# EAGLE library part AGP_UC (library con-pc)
AGP:UC Slot AMP connctor 145376 >PCT-GF40< 132 Position 1mm, card edge connector Drawing No: C-145263 Source: http://ecommas.tycoelectronics.com .. ENG_CD_145376_D.pdf

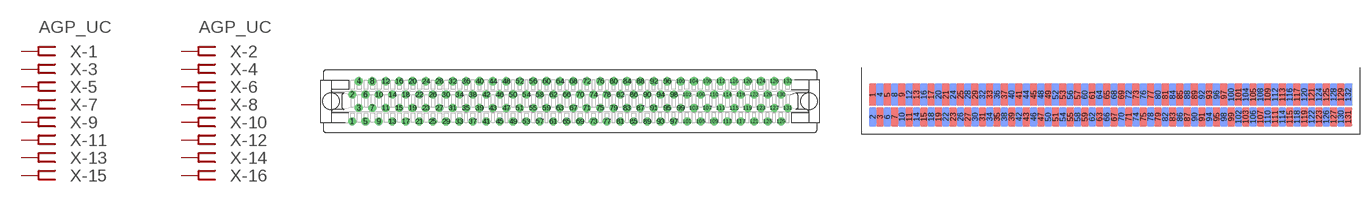
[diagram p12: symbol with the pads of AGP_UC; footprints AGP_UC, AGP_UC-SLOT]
Designator prefix X; gates -1=FEMRVAL -2=FEMRVAL -3=FEMREC -4=FEMREC -5=FEMREC -6=FEMREC -7=FEMREC -8=FEMREC -9=FEMREC -10=FEMREC -11=FEMREC -12=FEMREC -13=FEMREC -14=FEMREC -15=FEMREC -16=FEMREC -17=FEMREC -18=FEMREC -19=FEMREC -20=FEMREC -21=FEMREC -22=FEMREC -23=FEMREC -24=FEMREC -25=FEMREC -26=FEMREC -27=FEMREC -28=FEMREC -29=FEMREC -30=FEMREC -31=FEMREC -32=FEMREC -33=FEMREC -34=FEMREC -35=FEMREC -36=FEMREC -37=FEMREC -38=FEMREC -39=FEMREC -40=FEMREC -41=FEMREC -42=FEMREC -43=FEMREC -44=FEMREC -45=FEMREC -46=FEMREC -47=FEMREC -48=FEMREC -49=FEMREC -50=FEMREC -51=FEMREC -52=FEMREC -53=FEMREC -54=FEMREC -55=FEMREC -56=FEMREC -57=FEMREC -58=FEMREC -59=FEMREC -60=FEMREC -61=FEMREC -62=FEMREC -63=FEMREC -64=FEMREC -65=FEMREC -66=FEMREC -67=FEMREC -68=FEMREC -69=FEMREC -70=FEMREC -71=FEMREC -72=FEMREC -73=FEMREC -74=FEMREC -75=FEMREC -76=FEMREC -77=FEMREC -78=FEMREC -79=FEMREC -80=FEMREC -81=FEMREC -82=FEMREC -83=FEMREC -84=FEMREC -85=FEMREC -86=FEMREC -87=FEMREC -88=FEMREC -89=FEMREC -90=FEMREC -91=FEMREC -92=FEMREC -93=FEMREC -94=FEMREC -95=FEMREC -96=FEMREC -97=FEMREC -98=FEMREC -99=FEMREC -100=FEMREC -101=FEMREC -102=FEMREC -103=FEMREC -104=FEMREC -105=FEMREC -106=FEMREC -107=FEMREC -108=FEMREC -109=FEMREC -110=FEMREC -111=FEMREC -112=FEMREC -113=FEMREC -114=FEMREC -115=FEMREC -116=FEMREC -117=FEMREC -118=FEMREC -119=FEMREC -120=FEMREC -121=FEMREC -122=FEMREC -123=FEMREC -124=FEMREC -125=FEMREC -126=FEMREC -127=FEMREC -128=FEMREC -129=FEMREC -130=FEMREC -131=FEMREC -132=FEMREC

## AGP_UC  [AGP_UC]
1  -1:P  pas
2  -2:P  pas
3  -3:P  pas
4  -4:P  pas
5  -5:P  pas
6  -6:P  pas
7  -7:P  pas
8  -8:P  pas
9  -9:P  pas
10  -10:P  pas
11  -11:P  pas
12  -12:P  pas
13  -13:P  pas
14  -14:P  pas
15  -15:P  pas
16  -16:P  pas
17  -17:P  pas
18  -18:P  pas
19  -19:P  pas
20  -20:P  pas
21  -21:P  pas
22  -22:P  pas
23  -23:P  pas
24  -24:P  pas
25  -25:P  pas
26  -26:P  pas
27  -27:P  pas
28  -28:P  pas
29  -29:P  pas
30  -30:P  pas
31  -31:P  pas
32  -32:P  pas
33  -33:P  pas
34  -34:P  pas
35  -35:P  pas
36  -36:P  pas
37  -37:P  pas
38  -38:P  pas
39  -39:P  pas
40  -40:P  pas
41  -41:P  pas
42  -42:P  pas
43  -43:P  pas
44  -44:P  pas
45  -45:P  pas
46  -46:P  pas
47  -47:P  pas
48  -48:P  pas
49  -49:P  pas
50  -50:P  pas
51  -51:P  pas
52  -52:P  pas
53  -53:P  pas
54  -54:P  pas
55  -55:P  pas
56  -56:P  pas
57  -57:P  pas
58  -58:P  pas
59  -59:P  pas
60  -60:P  pas
61  -61:P  pas
62  -62:P  pas
63  -63:P  pas
64  -64:P  pas
65  -65:P  pas
66  -66:P  pas
67  -67:P  pas
68  -68:P  pas
69  -69:P  pas
70  -70:P  pas
71  -71:P  pas
72  -72:P  pas
73  -73:P  pas
74  -74:P  pas
75  -75:P  pas
76  -76:P  pas
77  -77:P  pas
78  -78:P  pas
79  -79:P  pas
80  -80:P  pas
81  -81:P  pas
82  -82:P  pas
83  -83:P  pas
84  -84:P  pas
85  -85:P  pas
86  -86:P  pas
87  -87:P  pas
88  -88:P  pas
89  -89:P  pas
90  -90:P  pas
91  -91:P  pas
92  -92:P  pas
93  -93:P  pas
94  -94:P  pas
95  -95:P  pas
96  -96:P  pas
97  -97:P  pas
98  -98:P  pas
99  -99:P  pas
100  -100:P  pas
101  -101:P  pas
102  -102:P  pas
103  -103:P  pas
104  -104:P  pas
105  -105:P  pas
106  -106:P  pas
107  -107:P  pas
108  -108:P  pas
109  -109:P  pas
110  -110:P  pas
111  -111:P  pas
112  -112:P  pas
113  -113:P  pas
114  -114:P  pas
115  -115:P  pas
116  -116:P  pas
117  -117:P  pas
118  -118:P  pas
119  -119:P  pas
120  -120:P  pas
121  -121:P  pas
122  -122:P  pas
123  -123:P  pas
124  -124:P  pas
125  -125:P  pas
126  -126:P  pas
127  -127:P  pas
128  -128:P  pas
129  -129:P  pas
130  -130:P  pas
131  -131:P  pas
132  -132:P  pas

## AGP_UC-SLOT  [AGP_UC-SLOT]
Pads as for AGP_UC

## Footprint AGP_UC (pad centres in mm)
AGP:UC Slot AMP connctor 145376 >PCT-GF40< 132 Position 1mm, card edge connector Drawing No: C-145263 Source: http://ecommas.tycoelectronics.com .. ENG_CD_145376_D.pdf
drill 0.7 pad 1.1 round: 1 0,-3; 2 0,1; 3 1,-1; 4 1,3; 5 2,-3; 6 2,1; 7 3,-1; 8 3,3; 9 4,-3; 10 4,1; 11 5,-1; 12 5,3; 13 6,-3; 14 6,1; 15 7,-1; 16 7,3; 17 8,-3; 18 8,1; 19 9,-1; 20 9,3; 21 10,-3; 22 10,1; 23 11,-1; 24 11,3; 25 12,-3; 26 12,1; 27 13,-1; 28 13,3; 29 14,-3; 30 14,1; 31 15,-1; 32 15,3; 33 16,-3; 34 16,1; 35 17,-1; 36 17,3; 37 18,-3; 38 18,1; 39 19,-1; 40 19,3; 41 20,-3; 42 20,1; 43 21,-1; 44 21,3; 45 22,-3; 46 22,1; 47 23,-1; 48 23,3; 49 24,-3; 50 24,1; 51 25,-1; 52 25,3; 53 26,-3; 54 26,1; 55 27,-1; 56 27,3; 57 28,-3; 58 28,1; 59 29,-1; 60 29,3; 61 30,-3; 62 30,1; 63 31,-1; 64 31,3; 65 32,-3; 66 32,1; 67 33,-1; 68 33,3; 69 34,-3; 70 34,1; 71 35,-1; 72 35,3; 73 36,-3; 74 36,1; 75 37,-1; 76 37,3; 77 38,-3; 78 38,1; 79 39,-1; 80 39,3; 81 40,-3; 82 40,1; 83 41,-1; 84 41,3; 85 42,-3; 86 42,1; 87 43,-1; 88 43,3; 89 44,-3; 90 44,1; 91 45,-1; 92 45,3; 93 46,-3; 94 46,1; 95 47,-1; 96 47,3; 97 48,-3; 98 48,1; 99 49,-1; 100 49,3; 101 50,-3; 102 50,1; 103 51,-1; 104 51,3; 105 52,-3; 106 52,1; 107 53,-1; 108 53,3; 109 54,-3; 110 54,1; 111 55,-1; 112 55,3; 113 56,-3; 114 56,1; 115 57,-1; 116 57,3; 117 58,-3; 118 58,1; 119 59,-1; 120 59,3; 121 60,-3; 122 60,1; 123 61,-1; 124 61,3; 125 62,-3; 126 62,1; 127 63,-1; 128 63,3; 129 64,-3; 130 64,1; 131 65,-1; 132 65,3
hole 2.5 at -3.14,0
hole 2.5 at 68.14,0

## Footprint AGP_UC-SLOT (pad centres in mm)
AGP:UC 132 Position 1mm Card connector Drawing No: C-145376 Source: http://ecommas.tycoelectronics.com .. ENG_CD_145376_D.pdf
smd 1.09 x 3.09: 1 1.54,5.46; 5 3.54,5.46; 9 5.54,5.46; 13 7.54,5.46; 17 9.54,5.46; 21 11.54,5.46; 25 13.54,5.46; 29 15.54,5.46; 33 17.54,5.46; 37 19.54,5.46; 41 21.54,5.46; 45 23.54,5.46; 49 25.54,5.46; 53 27.54,5.46; 57 29.54,5.46; 61 31.54,5.46; 65 33.54,5.46; 69 35.54,5.46; 73 37.54,5.46; 77 39.54,5.46; 81 41.54,5.46; 85 43.54,5.46; 89 45.54,5.46; 93 47.54,5.46; 97 49.54,5.46; 101 51.54,5.46; 105 53.54,5.46; 109 55.54,5.46; 113 57.54,5.46; 117 59.54,5.46; 121 61.54,5.46; 125 63.54,5.46; 129 65.54,5.46
smd 1.09 x 2.56 bottom: 2 1.54,2.42; 6 3.54,2.42; 10 5.54,2.42; 14 7.54,2.42; 18 9.54,2.42; 22 11.54,2.42; 26 13.54,2.42; 30 15.54,2.42; 34 17.54,2.42; 38 19.54,2.42; 42 21.54,2.42; 46 23.54,2.42; 50 25.54,2.42; 54 27.54,2.42; 58 29.54,2.42; 62 31.54,2.42; 66 33.54,2.42; 70 35.54,2.42; 74 37.54,2.42; 78 39.54,2.42; 82 41.54,2.42; 86 43.54,2.42; 90 45.54,2.42; 94 47.54,2.42; 98 49.54,2.42; 102 51.54,2.42; 106 53.54,2.42; 110 55.54,2.42; 114 57.54,2.42; 118 59.54,2.42; 122 61.54,2.42; 126 63.54,2.42; 130 65.54,2.42
smd 1.09 x 2.56: 3 2.54,2.42; 7 4.54,2.42; 11 6.54,2.42; 15 8.54,2.42; 19 10.54,2.42; 23 12.54,2.42; 27 14.54,2.42; 31 16.54,2.42; 35 18.54,2.42; 39 20.54,2.42; 43 22.54,2.42; 47 24.54,2.42; 51 26.54,2.42; 55 28.54,2.42; 59 30.54,2.42; 63 32.54,2.42; 67 34.54,2.42; 71 36.54,2.42; 75 38.54,2.42; 79 40.54,2.42; 83 42.54,2.42; 87 44.54,2.42; 91 46.54,2.42; 95 48.54,2.42; 99 50.54,2.42; 103 52.54,2.42; 107 54.54,2.42; 111 56.54,2.42; 115 58.54,2.42; 119 60.54,2.42; 123 62.54,2.42; 127 64.54,2.42; 131 66.54,2.42
smd 1.09 x 3.09 bottom: 4 2.54,5.46; 8 4.54,5.46; 12 6.54,5.46; 16 8.54,5.46; 20 10.54,5.46; 24 12.54,5.46; 28 14.54,5.46; 32 16.54,5.46; 36 18.54,5.46; 40 20.54,5.46; 44 22.54,5.46; 48 24.54,5.46; 52 26.54,5.46; 56 28.54,5.46; 60 30.54,5.46; 64 32.54,5.46; 68 34.54,5.46; 72 36.54,5.46; 76 38.54,5.46; 80 40.54,5.46; 84 42.54,5.46; 88 44.54,5.46; 92 46.54,5.46; 96 48.54,5.46; 100 50.54,5.46; 104 52.54,5.46; 108 54.54,5.46; 112 56.54,5.46; 116 58.54,5.46; 120 60.54,5.46; 124 62.54,5.46; 128 64.54,5.46; 132 66.54,5.46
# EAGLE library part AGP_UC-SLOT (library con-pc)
AGP:UC Slot AMP connctor 145376 >PCT-GF40< 132 Position 1mm, card edge connector Drawing No: C-145263 Source: http://ecommas.tycoelectronics.com .. ENG_CD_145376_D.pdf

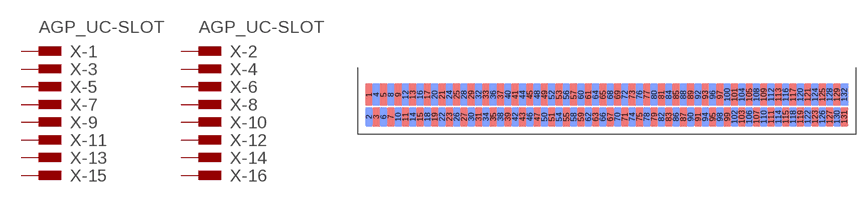
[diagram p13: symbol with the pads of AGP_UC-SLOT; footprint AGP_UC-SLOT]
Designator prefix X; gates -1=MALEVAL -2=MALEVAL -3=MALE -4=MALE -5=MALE -6=MALE -7=MALE -8=MALE -9=MALE -10=MALE -11=MALE -12=MALE -13=MALE -14=MALE -15=MALE -16=MALE -17=MALE -18=MALE -19=MALE -20=MALE -21=MALE -22=MALE -23=MALE -24=MALE -25=MALE -26=MALE -27=MALE -28=MALE -29=MALE -30=MALE -31=MALE -32=MALE -33=MALE -34=MALE -35=MALE -36=MALE -37=MALE -38=MALE -39=MALE -40=MALE -41=MALE -42=MALE -43=MALE -44=MALE -45=MALE -46=MALE -47=MALE -48=MALE -49=MALE -50=MALE -51=MALE -52=MALE -53=MALE -54=MALE -55=MALE -56=MALE -57=MALE -58=MALE -59=MALE -60=MALE -61=MALE -62=MALE -63=MALE -64=MALE -65=MALE -66=MALE -67=MALE -68=MALE -69=MALE -70=MALE -71=MALE -72=MALE -73=MALE -74=MALE -75=MALE -76=MALE -77=MALE -78=MALE -79=MALE -80=MALE -81=MALE -82=MALE -83=MALE -84=MALE -85=MALE -86=MALE -87=MALE -88=MALE -89=MALE -90=MALE -91=MALE -92=MALE -93=MALE -94=MALE -95=MALE -96=MALE -97=MALE -98=MALE -99=MALE -100=MALE -101=MALE -102=MALE -103=MALE -104=MALE -105=MALE -106=MALE -107=MALE -108=MALE -109=MALE -110=MALE -111=MALE -112=MALE -113=MALE -114=MALE -115=MALE -116=MALE -117=MALE -118=MALE -119=MALE -120=MALE -121=MALE -122=MALE -123=MALE -124=MALE -125=MALE -126=MALE -127=MALE -128=MALE -129=MALE -130=MALE -131=MALE -132=MALE

## AGP_UC-SLOT  [AGP_UC-SLOT]
1  -1:P  pas
2  -2:P  pas
3  -3:P  pas
4  -4:P  pas
5  -5:P  pas
6  -6:P  pas
7  -7:P  pas
8  -8:P  pas
9  -9:P  pas
10  -10:P  pas
11  -11:P  pas
12  -12:P  pas
13  -13:P  pas
14  -14:P  pas
15  -15:P  pas
16  -16:P  pas
17  -17:P  pas
18  -18:P  pas
19  -19:P  pas
20  -20:P  pas
21  -21:P  pas
22  -22:P  pas
23  -23:P  pas
24  -24:P  pas
25  -25:P  pas
26  -26:P  pas
27  -27:P  pas
28  -28:P  pas
29  -29:P  pas
30  -30:P  pas
31  -31:P  pas
32  -32:P  pas
33  -33:P  pas
34  -34:P  pas
35  -35:P  pas
36  -36:P  pas
37  -37:P  pas
38  -38:P  pas
39  -39:P  pas
40  -40:P  pas
41  -41:P  pas
42  -42:P  pas
43  -43:P  pas
44  -44:P  pas
45  -45:P  pas
46  -46:P  pas
47  -47:P  pas
48  -48:P  pas
49  -49:P  pas
50  -50:P  pas
51  -51:P  pas
52  -52:P  pas
53  -53:P  pas
54  -54:P  pas
55  -55:P  pas
56  -56:P  pas
57  -57:P  pas
58  -58:P  pas
59  -59:P  pas
60  -60:P  pas
61  -61:P  pas
62  -62:P  pas
63  -63:P  pas
64  -64:P  pas
65  -65:P  pas
66  -66:P  pas
67  -67:P  pas
68  -68:P  pas
69  -69:P  pas
70  -70:P  pas
71  -71:P  pas
72  -72:P  pas
73  -73:P  pas
74  -74:P  pas
75  -75:P  pas
76  -76:P  pas
77  -77:P  pas
78  -78:P  pas
79  -79:P  pas
80  -80:P  pas
81  -81:P  pas
82  -82:P  pas
83  -83:P  pas
84  -84:P  pas
85  -85:P  pas
86  -86:P  pas
87  -87:P  pas
88  -88:P  pas
89  -89:P  pas
90  -90:P  pas
91  -91:P  pas
92  -92:P  pas
93  -93:P  pas
94  -94:P  pas
95  -95:P  pas
96  -96:P  pas
97  -97:P  pas
98  -98:P  pas
99  -99:P  pas
100  -100:P  pas
101  -101:P  pas
102  -102:P  pas
103  -103:P  pas
104  -104:P  pas
105  -105:P  pas
106  -106:P  pas
107  -107:P  pas
108  -108:P  pas
109  -109:P  pas
110  -110:P  pas
111  -111:P  pas
112  -112:P  pas
113  -113:P  pas
114  -114:P  pas
115  -115:P  pas
116  -116:P  pas
117  -117:P  pas
118  -118:P  pas
119  -119:P  pas
120  -120:P  pas
121  -121:P  pas
122  -122:P  pas
123  -123:P  pas
124  -124:P  pas
125  -125:P  pas
126  -126:P  pas
127  -127:P  pas
128  -128:P  pas
129  -129:P  pas
130  -130:P  pas
131  -131:P  pas
132  -132:P  pas

## Footprint AGP_UC-SLOT (pad centres in mm)
AGP:UC 132 Position 1mm Card connector Drawing No: C-145376 Source: http://ecommas.tycoelectronics.com .. ENG_CD_145376_D.pdf
smd 1.09 x 3.09: 1 1.54,5.46; 5 3.54,5.46; 9 5.54,5.46; 13 7.54,5.46; 17 9.54,5.46; 21 11.54,5.46; 25 13.54,5.46; 29 15.54,5.46; 33 17.54,5.46; 37 19.54,5.46; 41 21.54,5.46; 45 23.54,5.46; 49 25.54,5.46; 53 27.54,5.46; 57 29.54,5.46; 61 31.54,5.46; 65 33.54,5.46; 69 35.54,5.46; 73 37.54,5.46; 77 39.54,5.46; 81 41.54,5.46; 85 43.54,5.46; 89 45.54,5.46; 93 47.54,5.46; 97 49.54,5.46; 101 51.54,5.46; 105 53.54,5.46; 109 55.54,5.46; 113 57.54,5.46; 117 59.54,5.46; 121 61.54,5.46; 125 63.54,5.46; 129 65.54,5.46
smd 1.09 x 2.56 bottom: 2 1.54,2.42; 6 3.54,2.42; 10 5.54,2.42; 14 7.54,2.42; 18 9.54,2.42; 22 11.54,2.42; 26 13.54,2.42; 30 15.54,2.42; 34 17.54,2.42; 38 19.54,2.42; 42 21.54,2.42; 46 23.54,2.42; 50 25.54,2.42; 54 27.54,2.42; 58 29.54,2.42; 62 31.54,2.42; 66 33.54,2.42; 70 35.54,2.42; 74 37.54,2.42; 78 39.54,2.42; 82 41.54,2.42; 86 43.54,2.42; 90 45.54,2.42; 94 47.54,2.42; 98 49.54,2.42; 102 51.54,2.42; 106 53.54,2.42; 110 55.54,2.42; 114 57.54,2.42; 118 59.54,2.42; 122 61.54,2.42; 126 63.54,2.42; 130 65.54,2.42
smd 1.09 x 2.56: 3 2.54,2.42; 7 4.54,2.42; 11 6.54,2.42; 15 8.54,2.42; 19 10.54,2.42; 23 12.54,2.42; 27 14.54,2.42; 31 16.54,2.42; 35 18.54,2.42; 39 20.54,2.42; 43 22.54,2.42; 47 24.54,2.42; 51 26.54,2.42; 55 28.54,2.42; 59 30.54,2.42; 63 32.54,2.42; 67 34.54,2.42; 71 36.54,2.42; 75 38.54,2.42; 79 40.54,2.42; 83 42.54,2.42; 87 44.54,2.42; 91 46.54,2.42; 95 48.54,2.42; 99 50.54,2.42; 103 52.54,2.42; 107 54.54,2.42; 111 56.54,2.42; 115 58.54,2.42; 119 60.54,2.42; 123 62.54,2.42; 127 64.54,2.42; 131 66.54,2.42
smd 1.09 x 3.09 bottom: 4 2.54,5.46; 8 4.54,5.46; 12 6.54,5.46; 16 8.54,5.46; 20 10.54,5.46; 24 12.54,5.46; 28 14.54,5.46; 32 16.54,5.46; 36 18.54,5.46; 40 20.54,5.46; 44 22.54,5.46; 48 24.54,5.46; 52 26.54,5.46; 56 28.54,5.46; 60 30.54,5.46; 64 32.54,5.46; 68 34.54,5.46; 72 36.54,5.46; 76 38.54,5.46; 80 40.54,5.46; 84 42.54,5.46; 88 44.54,5.46; 92 46.54,5.46; 96 48.54,5.46; 100 50.54,5.46; 104 52.54,5.46; 108 54.54,5.46; 112 56.54,5.46; 116 58.54,5.46; 120 60.54,5.46; 124 62.54,5.46; 128 64.54,5.46; 132 66.54,5.46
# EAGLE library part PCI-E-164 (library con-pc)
Copy from con-pci_express(pci-e).lbr uploaded Mon Jul 2 10:15:25 2007 Library for PCI-Express x16 (PCI-E) connector. Includes connector and card edge pattern. Uploaded by JF Duval <jfduval@aqra.ca> from AQRA.ca

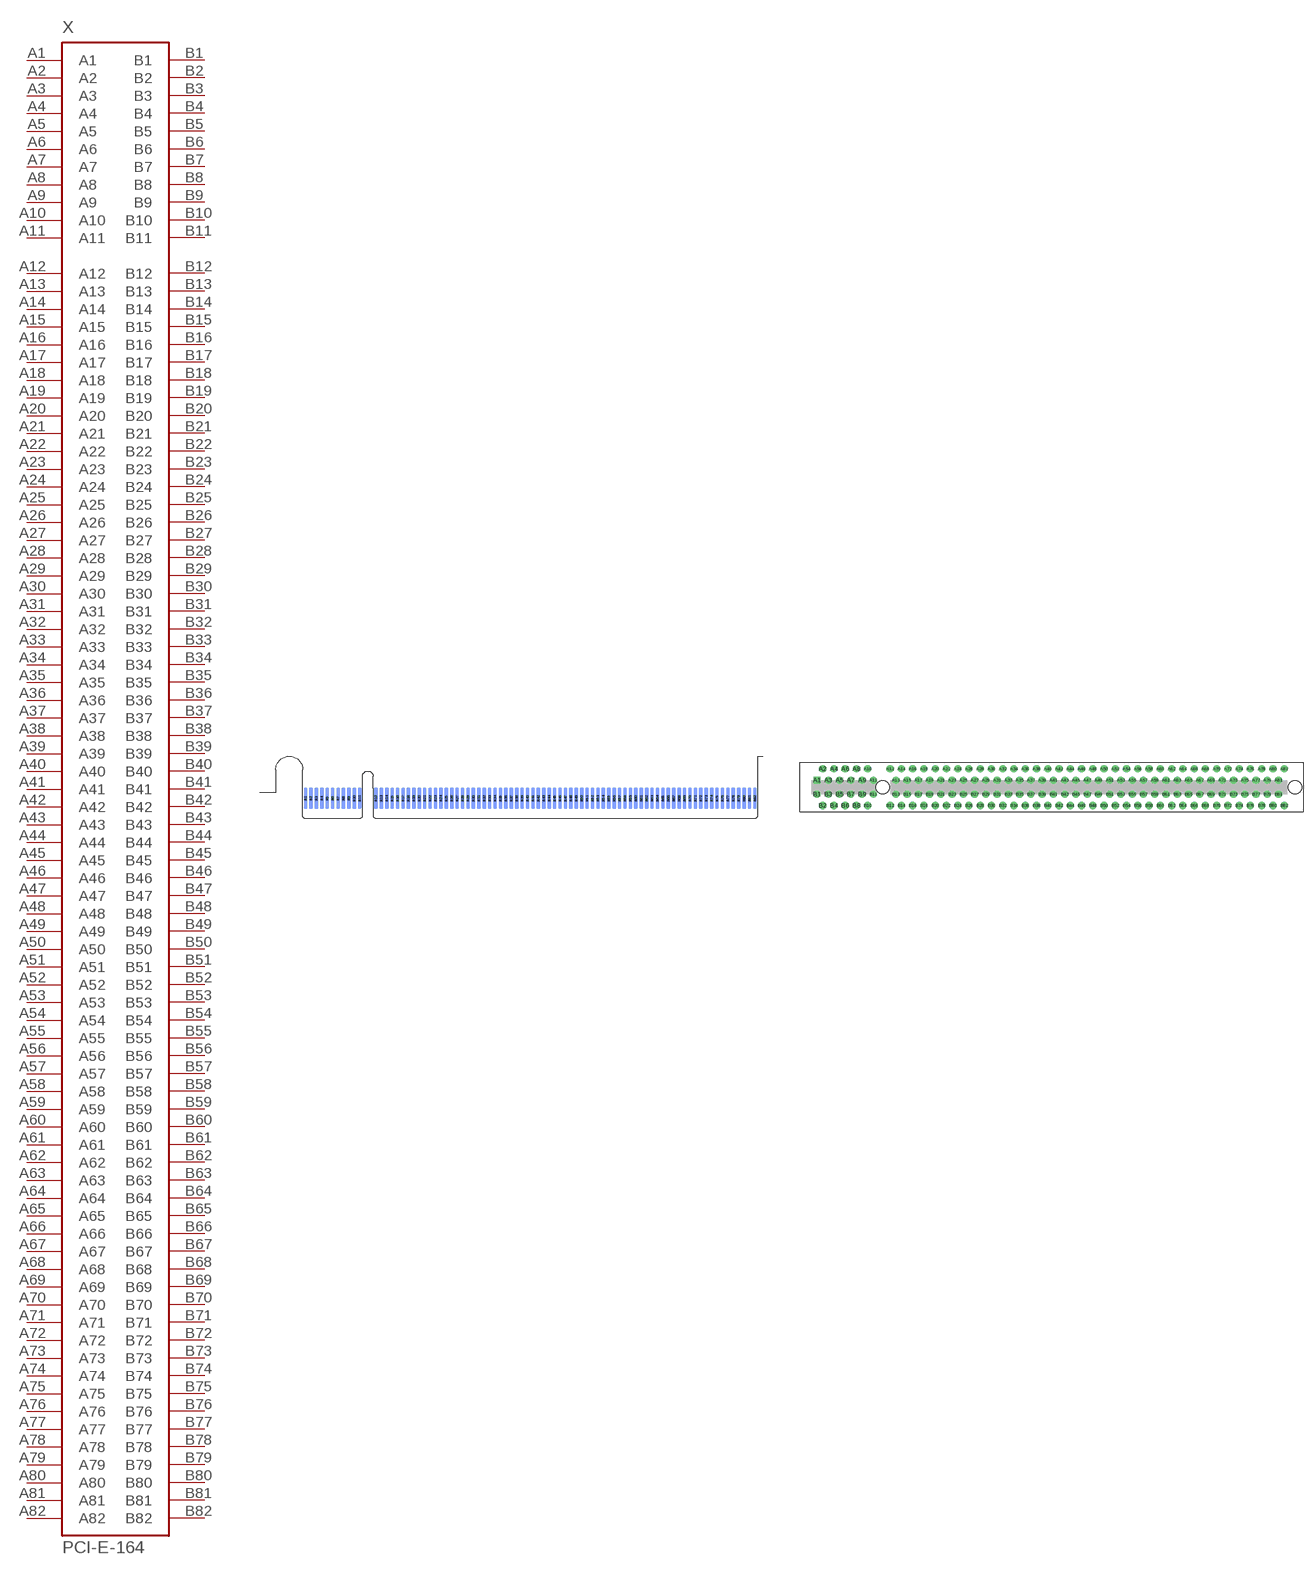
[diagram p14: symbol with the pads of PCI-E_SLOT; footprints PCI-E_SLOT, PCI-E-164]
Designator prefix X

## PCI-E-164SLOT  [PCI-E_SLOT]
A1  A1  pas
A2  A2  pas
A3  A3  pas
A4  A4  pas
A5  A5  pas
A6  A6  pas
A7  A7  pas
A8  A8  pas
A9  A9  pas
A10  A10  pas
A11  A11  pas
A12  A12  pas
A13  A13  pas
A14  A14  pas
A15  A15  pas
A16  A16  pas
A17  A17  pas
A18  A18  pas
A19  A19  pas
A20  A20  pas
A21  A21  pas
A22  A22  pas
A23  A23  pas
A24  A24  pas
A25  A25  pas
A26  A26  pas
A27  A27  pas
A28  A28  pas
A29  A29  pas
A30  A30  pas
A31  A31  pas
A32  A32  pas
A33  A33  pas
A34  A34  pas
A35  A35  pas
A36  A36  pas
A37  A37  pas
A38  A38  pas
A39  A39  pas
A40  A40  pas
A41  A41  pas
A42  A42  pas
A43  A43  pas
A44  A44  pas
A45  A45  pas
A46  A46  pas
A47  A47  pas
A48  A48  pas
A49  A49  pas
A50  A50  pas
A51  A51  pas
A52  A52  pas
A53  A53  pas
A54  A54  pas
A55  A55  pas
A56  A56  pas
A57  A57  pas
A58  A58  pas
A59  A59  pas
A60  A60  pas
A61  A61  pas
A62  A62  pas
A63  A63  pas
A64  A64  pas
A65  A65  pas
A66  A66  pas
A67  A67  pas
A68  A68  pas
A69  A69  pas
A70  A70  pas
A71  A71  pas
A72  A72  pas
A73  A73  pas
A74  A74  pas
A75  A75  pas
A76  A76  pas
A77  A77  pas
A78  A78  pas
A79  A79  pas
A80  A80  pas
A81  A81  pas
A82  A82  pas
B1  B1  pas
B2  B2  pas
B3  B3  pas
B4  B4  pas
B5  B5  pas
B6  B6  pas
B7  B7  pas
B8  B8  pas
B9  B9  pas
B10  B10  pas
B11  B11  pas
B12  B12  pas
B13  B13  pas
B14  B14  pas
B15  B15  pas
B16  B16  pas
B17  B17  pas
B18  B18  pas
B19  B19  pas
B20  B20  pas
B21  B21  pas
B22  B22  pas
B23  B23  pas
B24  B24  pas
B25  B25  pas
B26  B26  pas
B27  B27  pas
B28  B28  pas
B29  B29  pas
B30  B30  pas
B31  B31  pas
B32  B32  pas
B33  B33  pas
B34  B34  pas
B35  B35  pas
B36  B36  pas
B37  B37  pas
B38  B38  pas
B39  B39  pas
B40  B40  pas
B41  B41  pas
B42  B42  pas
B43  B43  pas
B44  B44  pas
B45  B45  pas
B46  B46  pas
B47  B47  pas
B48  B48  pas
B49  B49  pas
B50  B50  pas
B51  B51  pas
B52  B52  pas
B53  B53  pas
B54  B54  pas
B55  B55  pas
B56  B56  pas
B57  B57  pas
B58  B58  pas
B59  B59  pas
B60  B60  pas
B61  B61  pas
B62  B62  pas
B63  B63  pas
B64  B64  pas
B65  B65  pas
B66  B66  pas
B67  B67  pas
B68  B68  pas
B69  B69  pas
B70  B70  pas
B71  B71  pas
B72  B72  pas
B73  B73  pas
B74  B74  pas
B75  B75  pas
B76  B76  pas
B77  B77  pas
B78  B78  pas
B79  B79  pas
B80  B80  pas
B81  B81  pas
B82  B82  pas

## PCI-E-164SOCKET  [PCI-E-164]
Pads as for PCI-E_SLOT

## Footprint PCI-E_SLOT (pad centres in mm)
Copy from con-pci_express(pci-e).lbr uploaded Mon Jul 2 10:15:25 2007 with Finished-Layer Library for PCI-Express x16 (PCI-E) connector. Includes connector and card edge pattern. Uploaded by JF Duval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
smd 0.7 x 4 bottom: A1 8.5,3.75; A2 9.5,3.75; A3 10.5,3.75; A4 11.5,3.75; A5 12.5,3.75; A6 13.5,3.75; A7 14.5,3.75; A8 15.5,3.75; A9 16.5,3.75; A10 17.5,3.75; A11 18.5,3.75; A12 21.5,3.75; A13 22.5,3.75; A14 23.5,3.75; A15 24.5,3.75; A16 25.5,3.75; A17 26.5,3.75; A18 27.5,3.75; A19 28.5,3.75; A20 29.5,3.75; A21 30.5,3.75; A22 31.5,3.75; A23 32.5,3.75; A24 33.5,3.75; A25 34.5,3.75; A26 35.5,3.75; A27 36.5,3.75; A28 37.5,3.75; A29 38.5,3.75; A30 39.5,3.75; A31 40.5,3.75; A32 41.5,3.75; A33 42.5,3.75; A34 43.5,3.75; A35 44.5,3.75; A36 45.5,3.75; A37 46.5,3.75; A38 47.5,3.75; A39 48.5,3.75; A40 49.5,3.75; A41 50.5,3.75; A42 51.5,3.75; A43 52.5,3.75; A44 53.5,3.75; A45 54.5,3.75; A46 55.5,3.75; A47 56.5,3.75; A48 57.5,3.75; A49 58.5,3.75; A50 59.5,3.75; A51 60.5,3.75; A52 61.5,3.75; A53 62.5,3.75; A54 63.5,3.75; A55 64.5,3.75; A56 65.5,3.75; A57 66.5,3.75; A58 67.5,3.75; A59 68.5,3.75; A60 69.5,3.75; A61 70.5,3.75; A62 71.5,3.75; A63 72.5,3.75; A64 73.5,3.75; A65 74.5,3.75; A66 75.5,3.75; A67 76.5,3.75; A68 77.5,3.75; A69 78.5,3.75; A70 79.5,3.75; A71 80.5,3.75; A72 81.5,3.75; A73 82.5,3.75; A74 83.5,3.75; A75 84.5,3.75; A76 85.5,3.75; A77 86.5,3.75; A78 87.5,3.75; A79 88.5,3.75; A80 89.5,3.75; A81 90.5,3.75; A82 91.5,3.75
smd 0.7 x 4: B1 8.5,3.75; B2 9.5,3.75; B3 10.5,3.75; B4 11.5,3.75; B5 12.5,3.75; B6 13.5,3.75; B7 14.5,3.75; B8 15.5,3.75; B9 16.5,3.75; B10 17.5,3.75; B11 18.5,3.75; B12 21.5,3.75; B13 22.5,3.75; B14 23.5,3.75; B15 24.5,3.75; B16 25.5,3.75; B17 26.5,3.75; B18 27.5,3.75; B19 28.5,3.75; B20 29.5,3.75; B21 30.5,3.75; B22 31.5,3.75; B23 32.5,3.75; B24 33.5,3.75; B25 34.5,3.75; B26 35.5,3.75; B27 36.5,3.75; B28 37.5,3.75; B29 38.5,3.75; B30 39.5,3.75; B31 40.5,3.75; B32 41.5,3.75; B33 42.5,3.75; B34 43.5,3.75; B35 44.5,3.75; B36 45.5,3.75; B37 46.5,3.75; B38 47.5,3.75; B39 48.5,3.75; B40 49.5,3.75; B41 50.5,3.75; B42 51.5,3.75; B43 52.5,3.75; B44 53.5,3.75; B45 54.5,3.75; B46 55.5,3.75; B47 56.5,3.75; B48 57.5,3.75; B49 58.5,3.75; B50 59.5,3.75; B51 60.5,3.75; B52 61.5,3.75; B53 62.5,3.75; B54 63.5,3.75; B55 64.5,3.75; B56 65.5,3.75; B57 66.5,3.75; B58 67.5,3.75; B59 68.5,3.75; B60 69.5,3.75; B61 70.5,3.75; B62 71.5,3.75; B63 72.5,3.75; B64 73.5,3.75; B65 74.5,3.75; B66 75.5,3.75; B67 76.5,3.75; B68 77.5,3.75; B69 78.5,3.75; B70 79.5,3.75; B71 80.5,3.75; B72 81.5,3.75; B73 82.5,3.75; B74 83.5,3.75; B75 84.5,3.75; B76 85.5,3.75; B77 86.5,3.75; B78 87.5,3.75; B79 88.5,3.75; B80 89.5,3.75; B81 90.5,3.75; B82 91.5,3.75

## Footprint PCI-E-164 (pad centres in mm)
Copy from con-pci_express(pci-e).lbr uploaded Mon Jul 2 10:15:25 2007 Library for PCI-Express x16 (PCI-E) connector. Includes connector and card edge pattern. Uploaded by JF Duval <jfduval@aqra.ca>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
drill 0.7 pad 1.27 square: A1 -40,1.5
drill 0.7 pad 1.27 round: A2 -39,3.5; A3 -38,1.5; A4 -37,3.5; A5 -36,1.5; A6 -35,3.5; A7 -34,1.5; A8 -33,3.5; A9 -32,1.5; A10 -31,3.5; A11 -30,1.5; A12 -27,3.5; A13 -26,1.5; A14 -25,3.5; A15 -24,1.5; A16 -23,3.5; A17 -22,1.5; A18 -21,3.5; A19 -20,1.5; A20 -19,3.5; A21 -18,1.5; A22 -17,3.5; A23 -16,1.5; A24 -15,3.5; A25 -14,1.5; A26 -13,3.5; A27 -12,1.5; A28 -11,3.5; A29 -10,1.5; A30 -9,3.5; A31 -8,1.5; A32 -7,3.5; A33 -6,1.5; A34 -5,3.5; A35 -4,1.5; A36 -3,3.5; A37 -2,1.5; A38 -1,3.5; A39 0,1.5; A40 1,3.5; A41 2,1.5; A42 3,3.5; A43 4,1.5; A44 5,3.5; A45 6,1.5; A46 7,3.5; A47 8,1.5; A48 9,3.5; A49 10,1.5; A50 11,3.5; A51 12,1.5; A52 13,3.5; A53 14,1.5; A54 15,3.5; A55 16,1.5; A56 17,3.5; A57 18,1.5; A58 19,3.5; A59 20,1.5; A60 21,3.5; A61 22,1.5; A62 23,3.5; A63 24,1.5; A64 25,3.5; A65 26,1.5; A66 27,3.5; A67 28,1.5; A68 29,3.5; A69 30,1.5; A70 31,3.5; A71 32,1.5; A72 33,3.5; A73 34,1.5; A74 35,3.5; A75 36,1.5; A76 37,3.5; A77 38,1.5; A78 39,3.5; A79 40,1.5; A80 41,3.5; A81 42,1.5; A82 43,3.5; B1 -40,-1; B2 -39,-3; B3 -38,-1; B4 -37,-3; B5 -36,-1; B6 -35,-3; B7 -34,-1; B8 -33,-3; B9 -32,-1; B10 -31,-3; B11 -30,-1; B12 -27,-3; B13 -26,-1; B14 -25,-3; B15 -24,-1; B16 -23,-3; B17 -22,-1; B18 -21,-3; B19 -20,-1; B20 -19,-3; B21 -18,-1; B22 -17,-3; B23 -16,-1; B24 -15,-3; B25 -14,-1; B26 -13,-3; B27 -12,-1; B28 -11,-3; B29 -10,-1; B30 -9,-3; B31 -8,-1; B32 -7,-3; B33 -6,-1; B34 -5,-3; B35 -4,-1; B36 -3,-3; B37 -2,-1; B38 -1,-3; B39 0,-1; B40 1,-3; B41 2,-1; B42 3,-3; B43 4,-1; B44 5,-3; B45 6,-1; B46 7,-3; B47 8,-1; B48 9,-3; B49 10,-1; B50 11,-3; B51 12,-1; B52 13,-3; B53 14,-1; B54 15,-3; B55 16,-1; B56 17,-3; B57 18,-1; B58 19,-3; B59 20,-1; B60 21,-3; B61 22,-1; B62 23,-3; B63 24,-1; B64 25,-3; B65 26,-1; B66 27,-3; B67 28,-1; B68 29,-3; B69 30,-1; B70 31,-3; B71 32,-1; B72 33,-3; B73 34,-1; B74 35,-3; B75 36,-1; B76 37,-3; B77 38,-1; B78 39,-3; B79 40,-1; B80 41,-3; B81 42,-1; B82 43,-3
hole 2.35 at -28.35,0.25
hole 2.35 at 44.9,0.25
